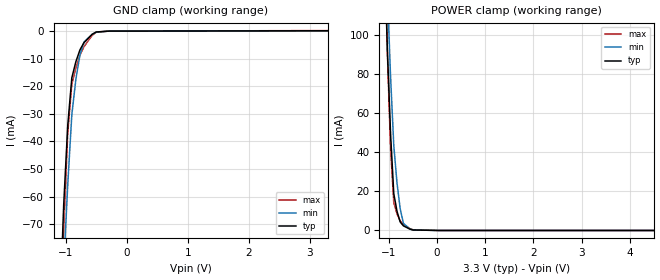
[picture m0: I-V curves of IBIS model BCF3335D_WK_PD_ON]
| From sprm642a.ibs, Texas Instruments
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|   Model Cell BCF3335D_WK_PD_ON
|BCF3335D_WK_PD_ON
[Model]   BCF3335D_WK_PD_ON
Model_type   Input
Polarity   Non-Inverting
Vinl =  0.8
Vinh =  2
C_comp   1.199917p   1.06526p   1.338254p
[Model Spec]
Vinl   0.8   0.8   0.8
Vinh   2   2   2
[Temperature Range]   25   155   -40
[Voltage Range]   3.3   2.97   3.63
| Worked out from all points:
|   GND clamp passes 1 mA (typ) near -0.55 V on its own axis
|   POWER clamp passes 1 mA (typ) near -0.59 V on its own axis
| Nom Voltages:
|   VDD=1.2, VDDS=3.3, VSS=0
| Min Voltages:
|   VDD=1.08, VDDS=2.97, VSS=0
| Max Voltages:
|   VDD=1.32, VDDS=3.63, VSS=0
[POWER_clamp]
|   voltage   I(typ)   I(min)   I(max)
-3.3V     2.333A     2.602A     3.083A
-1.1V     147.5mA    172.2mA    162.3mA
-1.033V   92.36mA    121.7mA    91.26mA
-966.7mV  49.51mA    78.85mA    41.92mA
-900mV    18.9mA     43.5mA     14.24mA
-833.3mV  9.846mA    24.38mA    8.545mA
-766.7mV  4.337mA    11.1mA     4.855mA
-700mV    2.37mA     3.662mA    3.173mA
-566.7mV  699.6uA    771.8uA    944.7uA
-500mV    248.7uA    286.4uA    332.8uA
33.33mV   0A         0A         0A
6.6V      0A         0A         0A
[GND_clamp]
|   voltage   I(typ)   I(min)   I(max)
-3.3V     -1.904A    -1.594A    -3.188A
-1.1V     -103.1mA   -119.1mA   -124mA
-1.033V   -62.89mA   -85.19mA   -71.77mA
-966.7mV  -34.16mA   -55.6mA    -36.88mA
-900mV    -16.94mA   -30.33mA   -19.31mA
-833.3mV  -11.09mA   -17.42mA   -13.31mA
-766.7mV  -6.831mA   -8.646mA   -8.753mA
-700mV    -4.166mA   -4.015mA   -5.633mA
-566.7mV  -1.181mA   -1.18mA    -1.554mA
-500mV    -336uA     -449.6uA   -399.2uA
-300mV    -27.98uA   -20.4uA    -40.75uA
3.3V      107.2uA    58.03uA    177.9uA
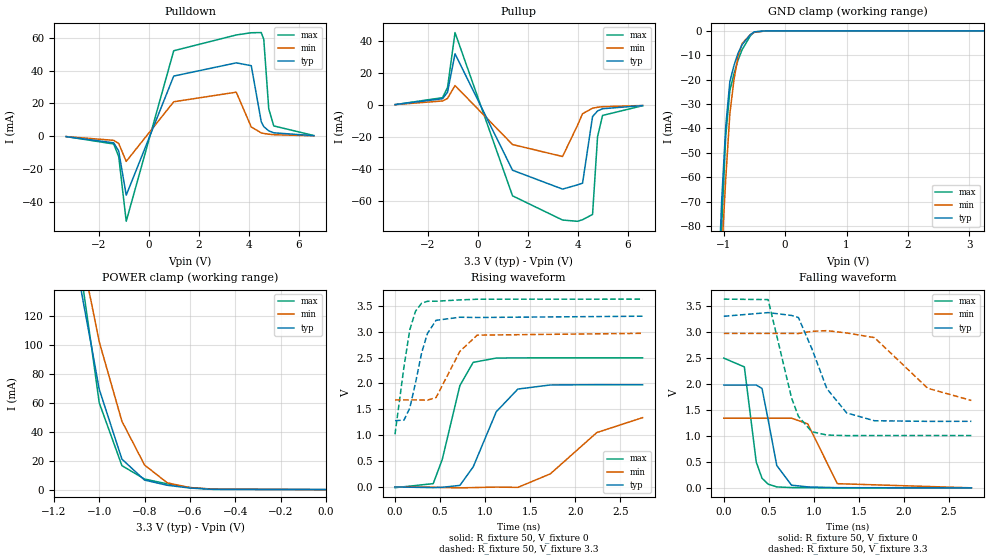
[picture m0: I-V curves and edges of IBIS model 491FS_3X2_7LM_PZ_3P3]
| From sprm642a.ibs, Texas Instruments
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|   Model Cell 491FS_3X2_7LM_PZ_3P3
|BQ0491FS_3X2_7LM_PZ_3P3
[Model]   491FS_3X2_7LM_PZ_3P3
Model_type   I/O
Polarity   Non-Inverting
Enable   Active-Low
Vinl =  1.25
Vinh =  1.65
Cref =  15.0001pF
Rref =  101.0000M
Vref =  0V
Vmeas =  1.65
C_comp   1.2p   1.2p   1.2p
[Model Spec]
Vinl   1.25   1.12   1.38
Vinh   1.65   1.45   1.75
[Temperature Range]   25   155   -40
[Voltage Range]   3.3   2.97   3.63
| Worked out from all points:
|   slope of the pulldown table from 0 to 0.495 V, typ, clamps not added: 22 ohm
|   slope of the pullup table from 0 to 0.495 V, typ, clamps not added: 26.9 ohm
|   GND clamp passes 1 mA (typ) near -0.53 V on its own axis
|   POWER clamp passes 1 mA (typ) near -0.59 V on its own axis
|   rising waveform, R_fixture 50, V_fixture 0: 20-80 % time 300ps typ, 528ps min, 211ps max; typ from 0 V to 1.98 V
|   rising waveform, R_fixture 50, V_fixture 3.3: 20-80 % time 158ps typ, 218ps min, 133ps max; typ from 1.28 V to 3.3 V
|   falling waveform, R_fixture 50, V_fixture 0: 20-80 % time 129ps typ, 180ps min, 108ps max; typ from 1.98 V to 0 V
|   falling waveform, R_fixture 50, V_fixture 3.3: 20-80 % time 290ps typ, 459ps min, 208ps max; typ from 3.3 V to 1.28 V
[POWER_clamp]
|   voltage   I(typ)   I(min)   I(max)
-3.3V     2.375A     2.63A      3.153A
-1.1V     156mA      180.2mA    173.4mA
-1.067V   127.2mA    154.3mA    135.6mA
-1.033V   98.41mA    128.4mA    97.92mA
-1V       69.61mA    102.5mA    60.2mA
-900mV    21.13mA    47.41mA    16.61mA
-800mV    6.576mA    17mA       7.309mA
-700mV    2.999mA    4.688mA    3.99mA
-600mV    1.087mA    1.404mA    1.425mA
-500mV    187uA      358.1uA    203.4uA
0V        311.4pA    5.945nA    272.3pA
[Pulldown]
|   voltage   I(typ)   I(min)   I(max)
-3.3V     -269.8uA   -248.1uA   -260.2uA
-1.4V     -4.056mA   -2.548mA   -4.78mA
-1.2V     -9.104mA   -4.482mA   -12.53mA
-900mV    -36.12mA   -15.43mA   -52.08mA
1V        36.78mA    21.07mA    52.28mA
3.5V      44.86mA    26.92mA    61.93mA
4.1V      43.14mA    5.644mA    63.29mA
4.5V      8.805mA    2.025mA    63.4mA
4.6V      5.861mA    1.678mA    59.29mA
4.8V      3.241mA    1.203mA    16.69mA
5V        2.072mA    900.6uA    6.272mA
6.6V      302.2uA    232.4uA    414.2uA
[Pullup]
|   voltage   I(typ)   I(min)   I(max)
-3.3V     296.7uA    284.3uA    270.4uA
-1.4V     3.996mA    2.582mA    4.655mA
-1.2V     8.017mA    4.201mA    10.97mA
-900mV    32.15mA    12.24mA    45.44mA
1.4V      -40.82mA   -24.72mA   -56.86mA
3.4V      -52.65mA   -32.22mA   -72.03mA
4V        -49.98mA   -12.64mA   -72.82mA
4.2V      -48.91mA   -5.386mA   -71.83mA
4.6V      -7.16mA    -1.965mA   -68.52mA
4.8V      -3.684mA   -1.373mA   -19.8mA
5V        -2.282mA   -1.01mA    -6.487mA
6.6V      -316.6uA   -254.8uA   -401.1uA
[GND_clamp]
|   voltage   I(typ)   I(min)   I(max)
-3.3V     -1.947A    -1.623A    -3.254A
-1.1V     -112mA     -127mA     -135.8mA
-1.033V   -69.61mA   -91.63mA   -80.19mA
-966.7mV  -39.23mA   -60.62mA   -43.11mA
-900mV    -20.86mA   -34.02mA   -24.52mA
-833.3mV  -14.26mA   -20.12mA   -17.61mA
-766.7mV  -9.194mA   -10.52mA   -12.01mA
-700mV    -5.668mA   -5.208mA   -7.706mA
-566.7mV  -1.566mA   -1.573mA   -2.055mA
-500mV    -402.3uA   -585.8uA   -459.7uA
-300mV    -821.9nA   -7.17uA    -404.6nA
3.233V    296.5pA    4.008uA    206.9pA
[Ramp]
| variable   typ   min   max
dV/dt_f   1.261151/0.2949777n  0.8125987/0.4793783n   1.631167/0.2132288n
dV/dt_r   1.201736/0.3055428n  0.8157639/0.5348505n   1.514657/0.207979n
R_load = 50
[Rising Waveform]
R_fixture = 50
V_fixture = 0
V_fixture_min = 0
V_fixture_max = 0
|   time   V(typ)   V(min)   V(max)
0s        -24.54uV   10.63uV    -14.63mV
424ps     -13.78mV   -3.257mV   63.95mV
524ps     -7.093mV   -11.97mV   527mV
720ps     29.58mV    -17.98mV   1.959V
868ps     387.7mV    -12.57mV   2.408V
1.124ns   1.453V     -3.016mV   2.491V
1.364ns   1.892V     -8.711mV   2.494V
1.724ns   1.971V     252.6mV    2.495V
2.24ns    1.976V     1.051V     2.495V
2.748ns   1.975V     1.339V     2.495V
[Rising Waveform]
R_fixture = 50
V_fixture = 3.3
V_fixture_min = 2.97
V_fixture_max = 3.63
|   time   V(typ)   V(min)   V(max)
0s        1.281V     1.682V     1.018V
100ps     1.292V     1.682V     2.327V
164ps     1.524V     1.682V     3.037V
228ps     2.014V     1.682V     3.398V
296ps     2.595V     1.681V     3.552V
360ps     2.966V     1.677V     3.588V
456ps     3.221V     1.728V     3.59V
720ps     3.28V      2.62V      3.615V
912ps     3.275V     2.934V     3.628V
2.748ns   3.3V       2.969V     3.63V
[Falling Waveform]
R_fixture = 50
V_fixture = 0
V_fixture_min = 0
V_fixture_max = 0
|   time   V(typ)   V(min)   V(max)
0s        1.977V     1.34V      2.495V
228ps     1.977V     1.34V      2.327V
360ps     1.978V     1.34V      497.8mV
424ps     1.912V     1.34V      186mV
492ps     1.313V     1.34V      71.31mV
588ps     429.9mV    1.34V      18.16mV
752ps     51.68mV    1.34V      5.391mV
932ps     18.34mV    1.231V     2.379mV
1.26ns    3.521mV    80.53mV    495.6uV
2.748ns   98.08uV    534.9uV    -8.176uV
[Falling Waveform]
R_fixture = 50
V_fixture = 3.3
V_fixture_min = 2.97
V_fixture_max = 3.63
|   time   V(typ)   V(min)   V(max)
0s        3.3V       2.97V      3.63V
492ps     3.371V     2.97V      3.621V
752ps     3.316V     2.97V      1.73V
828ps     3.276V     2.969V     1.377V
976ps     2.683V     3.01V      1.081V
1.144ns   1.907V     3.024V     1.016V
1.364ns   1.441V     2.979V     1.005V
1.672ns   1.291V     2.89V      1.006V
2.264ns   1.279V     1.915V     1.007V
2.748ns   1.28V      1.681V     1.006V
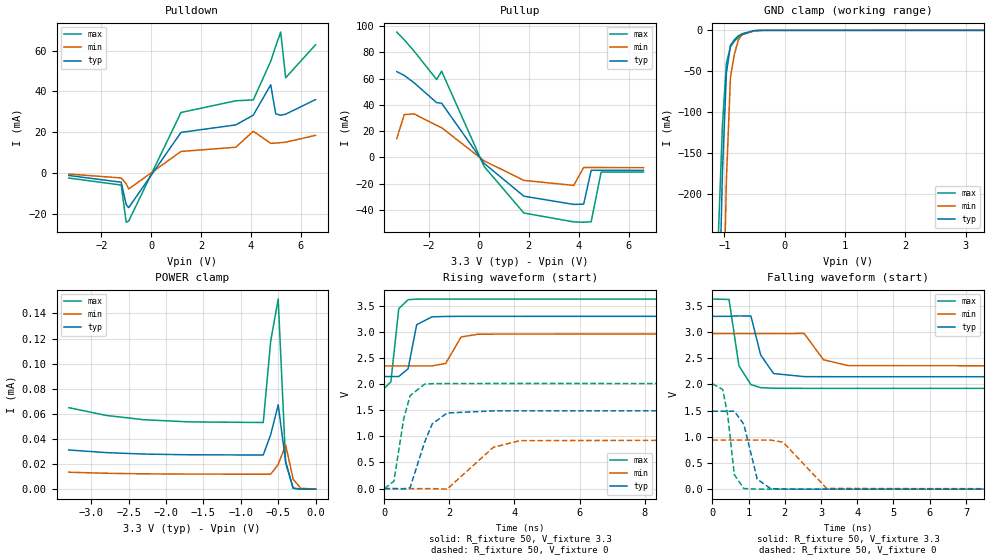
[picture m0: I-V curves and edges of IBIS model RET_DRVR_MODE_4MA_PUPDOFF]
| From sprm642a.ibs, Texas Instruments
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|   Model Cell RET_DRVR_MODE_4MA_PUPDOFF
|RET_DRVR_MODE_4MA_PUPDOFF
[Model]   RET_DRVR_MODE_4MA_PUPDOFF
Model_type   I/O
Polarity   Non-Inverting
Enable   Active-Low
Vinl =  0.8
Vinh =  2
Cref =  15.0000pF
Rref =  100.0000M
Vref =  0V
Vmeas =  1.65
C_comp   5.345208p   4.561426p   6.022817p
[Model Spec]
Vinl   0.8   0.8   0.8
Vinh   2   2   2
[Temperature Range]   25   155   -40
[Voltage Range]   3.3   2.97   3.63
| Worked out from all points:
|   slope of the pulldown table from 0 to 0.495 V, typ, clamps not added: 47.6 ohm
|   slope of the pullup table from 0 to 0.495 V, typ, clamps not added: 46.2 ohm
|   GND clamp passes 1 mA (typ) near -0.55 V on its own axis
|   rising waveform, R_fixture 50, V_fixture 3.3: 20-80 % time 194ps typ, 280ps min, 151ps max; typ from 2.15 V to 3.3 V
|   rising waveform, R_fixture 50, V_fixture 0: 20-80 % time 455ps typ, 811ps min, 333ps max; typ from 0 V to 1.49 V
|   falling waveform, R_fixture 50, V_fixture 3.3: 20-80 % time 263ps typ, 365ps min, 230ps max; typ from 3.3 V to 2.15 V
|   falling waveform, R_fixture 50, V_fixture 0: 20-80 % time 300ps typ, 541ps min, 197ps max; typ from 1.49 V to 0 V
| Nom Voltages:
|   BIASFET=3.3, VDD=1.2, VDDS=3.3, VSS=0
| Min Voltages:
|   BIASFET=2.97, VDD=1.08, VDDS=2.97, VSS=0
| Max Voltages:
|   BIASFET=3.63, VDD=1.32, VDDS=3.63, VSS=0
[POWER_clamp]
|   voltage   I(typ)   I(min)   I(max)
-3.3V     31.22uA    13.5uA     64.95uA
-2.8V     29.13uA    12.67uA    58.77uA
-2.3V     27.98uA    12.22uA    55.36uA
-1.7V     27.4uA     12.01uA    53.62uA
-700mV    27.24uA    11.95uA    53.12uA
-600mV    43.52uA    11.94uA    118.2uA
-500mV    67.2uA     19.79uA    151.5uA
-400mV    21.58uA    35.09uA    21.1uA
-300mV    927.4nA    7.958uA    611.4nA
-200mV    28.93nA    716.3nA    11.51nA
0V        696.9pA    39.48nA    568pA
[Pulldown]
|   voltage   I(typ)   I(min)   I(max)
-3.3V     -1.162mA   -442.5uA   -2.413mA
-1.2V     -4.448mA   -2.37mA    -5.833mA
-1V       -15.42mA   -5.267mA   -24.03mA
-900mV    -16.9mA    -7.758mA   -23.48mA
1.2V      19.95mA    10.62mA    29.71mA
3.4V      23.64mA    12.69mA    35.45mA
4.1V      28.41mA    20.51mA    35.87mA
4.8V      43.29mA    14.6mA     54.81mA
5V        29.04mA    14.73mA    62.21mA
5.2V      28.35mA    14.92mA    69.1mA
5.4V      28.9mA     15.16mA    46.73mA
6.6V      36.05mA    18.53mA    62.9mA
[Pullup]
|   voltage   I(typ)   I(min)   I(max)
-3.3V     65.33mA    14.31mA    95.47mA
-3V       62.41mA    32.57mA    89.6mA
-2.6V     56.73mA    33.05mA    80.83mA
-1.7V     41.66mA    24.3mA     59.29mA
-1.5V     41.23mA    22.57mA    65.63mA
200mV     -4.548mA   -2.626mA   -6.86mA
1.8V      -29.65mA   -17.6mA    -42.48mA
3.8V      -35.93mA   -21.45mA   -49.25mA
4.2V      -35.7mA    -7.748mA   -49.48mA
4.5V      -9.896mA   -7.768mA   -49.16mA
4.9V      -9.898mA   -7.8mA     -11.24mA
6.6V      -9.969mA   -7.94mA    -11.25mA
[GND_clamp]
|   voltage   I(typ)   I(min)   I(max)
-3.3V     -16.36A    -15.08A    -17.18A
-1.1V     -382.1mA   -717.8mA   -250.1mA
-1.033V   -173.3mA   -402.2mA   -116.4mA
-966.7mV  -52.02mA   -182.1mA   -39.81mA
-900mV    -18.21mA   -57.43mA   -20.34mA
-833.3mV  -11.36mA   -28.88mA   -13.17mA
-766.7mV  -6.618mA   -11.27mA   -8.134mA
-700mV    -3.983mA   -4.59mA    -5.247mA
-500mV    -328.3uA   -481.4uA   -374.5uA
-366.7mV  -15.94uA   -50.74uA   -14.83uA
3.3V      697pA      15.84uA    426.1pA
[Ramp]
| variable   typ   min   max
dV/dt_f 0.70108472/0.26467362n  0.3775134/0.36797817n  1.0337594/0.2297899n
dV/dt_r 0.90140012/0.45748411n 0.56935959/0.81782891n  1.2149327/0.33385389n
R_load = 50
[Rising Waveform]
R_fixture = 50
V_fixture = 3.3
V_fixture_min = 2.97
V_fixture_max = 3.63
|   time   V(typ)   V(min)   V(max)
0s        2.146V     2.35V      1.924V
197.7ps   2.146V     2.35V      2.043V
440.5ps   2.146V     2.35V      3.446V
728.2ps   2.296V     2.35V      3.618V
990.8ps   3.138V     2.35V      3.628V
1.46ns    3.289V     2.35V      3.63V
1.883ns   3.297V     2.397V     3.63V
2.357ns   3.299V     2.904V     3.63V
2.889ns   3.299V     2.958V     3.63V
20.14ns   3.3V       2.97V      3.63V
[Rising Waveform]
R_fixture = 50
V_fixture = 0
V_fixture_min = 0
V_fixture_max = 0
|   time   V(typ)   V(min)   V(max)
0s        0V         0V         0V
291.1ps   0V         0V         142.4mV
593.2ps   -7.748mV   0V         1.338V
789.3ps   16.48mV    0V         1.78V
1.231ns   882.3mV    0V         1.999V
1.47ns    1.239V     0V         2.01V
1.927ns   1.448V     -10.91mV   2.012V
3.351ns   1.488V     791.6mV    2.013V
4.174ns   1.489V     918.6mV    2.013V
20.01ns   1.489V     937.6mV    2.012V
[Falling Waveform]
R_fixture = 50
V_fixture = 3.3
V_fixture_min = 2.97
V_fixture_max = 3.63
|   time   V(typ)   V(min)   V(max)
0s        3.3V       2.97V      3.63V
460.3ps   3.3V       2.97V      3.623V
733.6ps   3.309V     2.97V      2.355V
1.064ns   3.305V     2.97V      1.997V
1.333ns   2.563V     2.97V      1.939V
1.689ns   2.208V     2.97V      1.926V
2.531ns   2.149V     2.974V     1.925V
3.07ns    2.148V     2.471V     1.925V
3.746ns   2.147V     2.359V     1.925V
20.14ns   2.146V     2.35V      1.925V
[Falling Waveform]
R_fixture = 50
V_fixture = 0
V_fixture_min = 0
V_fixture_max = 0
|   time   V(typ)   V(min)   V(max)
0s        1.489V     937.2mV    2.013V
287.6ps   1.489V     937.2mV    1.902V
423.7ps   1.489V     937.2mV    1.414V
606.4ps   1.489V     937.2mV    276.1mV
868.9ps   1.239V     937.2mV    12.33mV
1.239ns   190.6mV    937.2mV    0V
1.608ns   10.16mV    937mV      0V
1.952ns   2.09mV     897.9mV    0V
3.157ns   0V         12.74mV    0V
20.01ns   0V         0V         0V
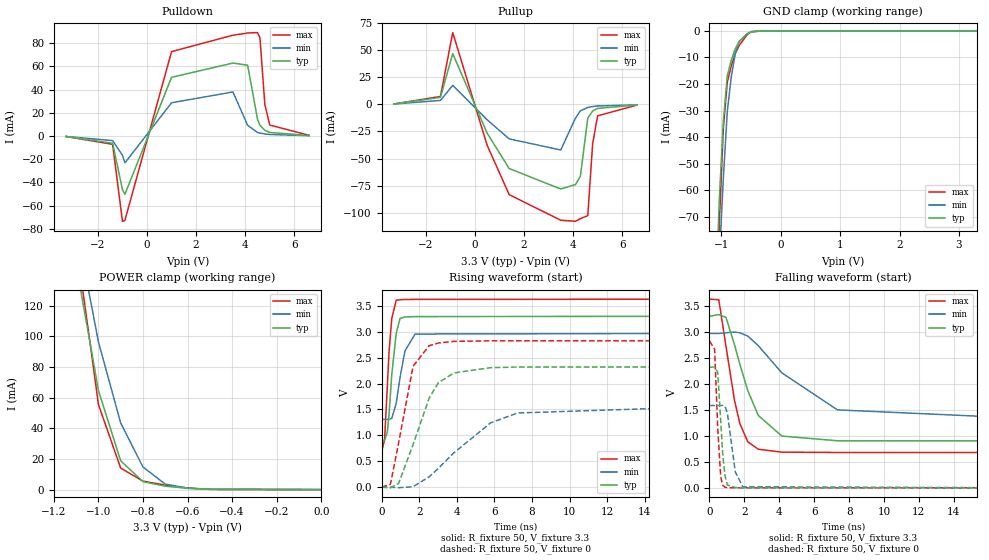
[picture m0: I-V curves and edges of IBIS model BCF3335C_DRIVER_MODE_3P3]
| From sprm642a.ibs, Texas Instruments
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|   Model Cell BCF3335C_DRIVER_MODE_3P3
|BCF3335C_DRIVER_MODE_3P3
[Model]   BCF3335C_DRIVER_MODE_3P3
Model_type   I/O
Polarity   Non-Inverting
Enable   Active-Low
Vinl =  0.8
Vinh =  2
Cref =  15.0000pF
Rref =  100.0000M
Vref =  0V
Vmeas =  1.65
C_comp   1.21278p   1.078036p   1.350148p
[Model Spec]
Vinl   0.8   0.8   0.8
Vinh   2   2   2
[Temperature Range]   25   155   -40
[Voltage Range]   3.3   2.97   3.63
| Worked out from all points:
|   slope of the pulldown table from 0 to 0.495 V, typ, clamps not added: 16.3 ohm
|   slope of the pullup table from 0 to 0.495 V, typ, clamps not added: 18.9 ohm
|   GND clamp passes 1 mA (typ) near -0.56 V on its own axis
|   POWER clamp passes 1 mA (typ) near -0.61 V on its own axis
|   rising waveform, R_fixture 50, V_fixture 3.3: 20-80 % time 324ps typ, 461ps min, 266ps max; typ from 0.904 V to 3.3 V
|   rising waveform, R_fixture 50, V_fixture 0: 20-80 % time 1.37ns typ, 3.07ns min, 863ps max; typ from 0 V to 2.32 V
|   falling waveform, R_fixture 50, V_fixture 3.3: 20-80 % time 1.44ns typ, 3.22ns min, 907ps max; typ from 3.3 V to 0.904 V
|   falling waveform, R_fixture 50, V_fixture 0: 20-80 % time 246ps typ, 378ps min, 201ps max; typ from 2.32 V to 0 V
| Nom Voltages:
|   VDD=1.2, VDDS=3.3, VSS=0
| Min Voltages:
|   VDD=1.08, VDDS=2.97, VSS=0
| Max Voltages:
|   VDD=1.32, VDDS=3.63, VSS=0
[POWER_clamp]
|   voltage   I(typ)   I(min)   I(max)
-3.3V     2.319A     2.596A     3.052A
-1.1V     147.6mA    172.2mA    162.5mA
-1.067V   120mA      147mA      126.9mA
-1.033V   92.39mA    121.8mA    91.25mA
-1V       64.8mA     96.55mA    55.64mA
-900mV    18.81mA    43.51mA    14.07mA
-800mV    5.217mA    14.79mA    5.52mA
-700mV    2.265mA    3.617mA    2.996mA
-600mV    818.1uA    964.5uA    1.072mA
-500mV    141.2uA    235.4uA    153.9uA
0V        61.2pA     4.167nA    14.64pA
[Pulldown]
|   voltage   I(typ)   I(min)   I(max)
-3.3V     -391.6uA   -361.2uA   -374.3uA
-1.4V     -6.232mA   -3.922mA   -7.12mA
-1V       -46.14mA   -16.61mA   -73.47mA
-900mV    -50.18mA   -23.11mA   -72.68mA
1V        50.59mA    28.67mA    72.75mA
3.5V      62.89mA    37.99mA    86.89mA
4.1V      61.03mA    9.214mA    88.75mA
4.5V      14.6mA     3.072mA    89.16mA
4.6V      9.297mA    2.529mA    84.77mA
4.8V      4.929mA    1.797mA    27.22mA
5V        3.1mA      1.339mA    9.48mA
6.6V      439.9uA    335.7uA    600uA
[Pullup]
|   voltage   I(typ)   I(min)   I(max)
-3.3V     459.5uA    394.7uA    413.2uA
-1.4V     6.562mA    3.722mA    7.377mA
-900mV    46.98mA    17.64mA    66.44mA
500mV     -26.44mA   -14.16mA   -37.6mA
1.4V      -59.25mA   -31.82mA   -83.37mA
3.5V      -78.14mA   -42.09mA   -107mA
4.1V      -74.05mA   -12.61mA   -108mA
4.3V      -66.33mA   -5.866mA   -105.6mA
4.6V      -12.76mA   -2.802mA   -102.8mA
4.8V      -6.084mA   -1.937mA   -36.14mA
5V        -3.668mA   -1.416mA   -10.53mA
6.6V      -489.4uA   -345.7uA   -614.6uA
[GND_clamp]
|   voltage   I(typ)   I(min)   I(max)
-3.3V     -1.89A     -1.587A    -3.158A
-1.1V     -103.2mA   -119.1mA   -124.2mA
-1.033V   -62.94mA   -85.23mA   -71.86mA
-966.7mV  -34.17mA   -55.63mA   -36.88mA
-900mV    -16.92mA   -30.33mA   -19.28mA
-833.3mV  -11.06mA   -17.41mA   -13.25mA
-766.7mV  -6.784mA   -8.632mA   -8.674mA
-700mV    -4.107mA   -3.993mA   -5.546mA
-566.7mV  -1.13mA    -1.153mA   -1.479mA
-500mV    -290.2uA   -424.2uA   -331.9uA
-300mV    -598.5nA   -5.196uA   -296.8nA
3.3V      61.2pA     6.786uA    8.136pA
[Ramp]
| variable   typ   min   max
dV/dt_f   1.461786/1.4476561n  1.0135907/3.246082n   1.7954386/0.91538426n
dV/dt_r  1.4029813/1.3750139n 0.95806656/3.0834157n  1.7045214/0.86702444n
R_load = 50
[Rising Waveform]
R_fixture = 50
V_fixture = 3.3
V_fixture_min = 2.97
V_fixture_max = 3.63
|   time   V(typ)   V(min)   V(max)
0s        903.7mV    1.309V     681.8mV
156.7ps   905.2mV    1.31V      916.3mV
297.1ps   1.058V     1.309V     1.912V
392.9ps   1.396V     1.308V     2.606V
537.9ps   2.175V     1.327V     3.254V
774.4ps   2.968V     1.615V     3.609V
976.8ps   3.255V     2.115V     3.618V
1.237ns   3.286V     2.626V     3.623V
1.778ns   3.293V     2.956V     3.625V
20.02ns   3.3V       2.97V      3.63V
[Rising Waveform]
R_fixture = 50
V_fixture = 0
V_fixture_min = 0
V_fixture_max = 0
|   time   V(typ)   V(min)   V(max)
0s        0V         0V         0V
464.7ps   -13.07mV   0V         54.97mV
902.2ps   72.68mV    -10.01mV   852.8mV
1.672ns   822.7mV    9.485mV    2.334V
2.527ns   1.72V      200.3mV    2.732V
3.029ns   2.022V     366.6mV    2.783V
3.856ns   2.206V     667.1mV    2.815V
5.794ns   2.307V     1.241V     2.825V
7.222ns   2.319V     1.432V     2.825V
20.01ns   2.321V     1.584V     2.825V
[Falling Waveform]
R_fixture = 50
V_fixture = 3.3
V_fixture_min = 2.97
V_fixture_max = 3.63
|   time   V(typ)   V(min)   V(max)
0s        3.3V       2.97V      3.63V
535.7ps   3.333V     2.97V      3.618V
947.9ps   3.277V     2.983V     2.717V
1.438ns   2.75V      2.998V     1.678V
1.743ns   2.375V     2.983V     1.235V
2.194ns   1.871V     2.92V      886mV
2.798ns   1.393V     2.734V     742.9mV
4.145ns   996.2mV    2.213V     687.1mV
7.332ns   905.7mV    1.5V       680.6mV
20.02ns   903.6mV    1.309V     680.8mV
[Falling Waveform]
R_fixture = 50
V_fixture = 0
V_fixture_min = 0
V_fixture_max = 0
|   time   V(typ)   V(min)   V(max)
0s        2.321V     1.584V     2.825V
295.7ps   2.323V     1.583V     2.667V
470.9ps   2.229V     1.583V     1.17V
643.4ps   1.299V     1.585V     215mV
753.8ps   669mV      1.586V     52.35mV
889ps     231.8mV    1.57V      12.31mV
1.029ns   54.15mV    1.429V     4.593mV
1.481ns   7.104mV    304.9mV    0V
1.915ns   2.84mV     19.68mV    0V
20.01ns   0V         0V         0V
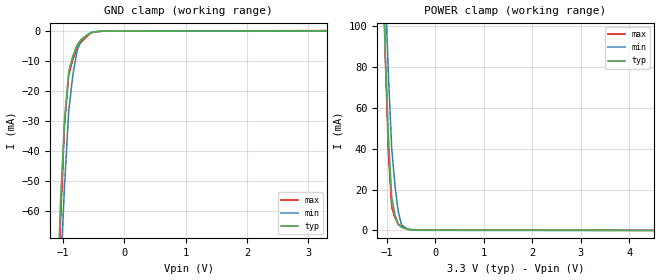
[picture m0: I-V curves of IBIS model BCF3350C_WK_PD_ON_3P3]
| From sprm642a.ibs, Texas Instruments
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|   Model Cell BCF3350C_WK_PD_ON_3P3
|BCF3350C_WK_PD_ON_3P3
[Model]   BCF3350C_WK_PD_ON_3P3
Model_type   Input
Polarity   Non-Inverting
Vinl =  0.8
Vinh =  2
C_comp   1.081618p   0.946736p   1.221412p
[Model Spec]
Vinl   0.8   0.8   0.8
Vinh   2   2   2
[Temperature Range]   25   155   -40
[Voltage Range]   3.3   2.97   3.63
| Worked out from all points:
|   GND clamp passes 1 mA (typ) near -0.58 V on its own axis
|   POWER clamp passes 1 mA (typ) near -0.64 V on its own axis
| Nom Voltages:
|   VDD=1.2, VDDS=3.3, VSS=0
| Min Voltages:
|   VDD=1.08, VDDS=2.97, VSS=0
| Max Voltages:
|   VDD=1.32, VDDS=3.63, VSS=0
[POWER_clamp]
|   voltage   I(typ)   I(min)   I(max)
-3.3V     2.318A     2.595A     3.049A
-1.1V     141.5mA    168mA      152.4mA
-1.033V   87.22mA    117.8mA    84.5mA
-966.7mV  45.46mA    75.19mA    37.47mA
-900mV    16.26mA    40.27mA    11.33mA
-833.3mV  7.927mA    21.99mA    6.203mA
-766.7mV  3.013mA    9.498mA    3.099mA
-700mV    1.521mA    2.801mA    2.021mA
-566.7mV  472.3uA    527.3uA    648.9uA
-366.7mV  111.4uA    66.02uA    181.9uA
6.6V      0A         0A         0A
[GND_clamp]
|   voltage   I(typ)   I(min)   I(max)
-3.3V     -1.888A    -1.585A    -3.154A
-1.1V     -95.79mA   -113.9mA   -112.1mA
-1.033V   -56.71mA   -80.31mA   -63.62mA
-966.7mV  -29.26mA   -51.23mA   -31.17mA
-900mV    -13.43mA   -26.68mA   -14.76mA
-833.3mV  -8.27mA    -14.79mA   -9.517mA
-766.7mV  -4.725mA   -6.876mA   -5.842mA
-700mV    -2.797mA   -2.931mA   -3.733mA
-566.7mV  -794.1uA   -808.3uA   -1.042mA
-500mV    -234.8uA   -305.8uA   -282.8uA
-366.7mV  -42.38uA   -46.42uA   -57.66uA
3.3V      107.2uA    55.45uA    177.9uA
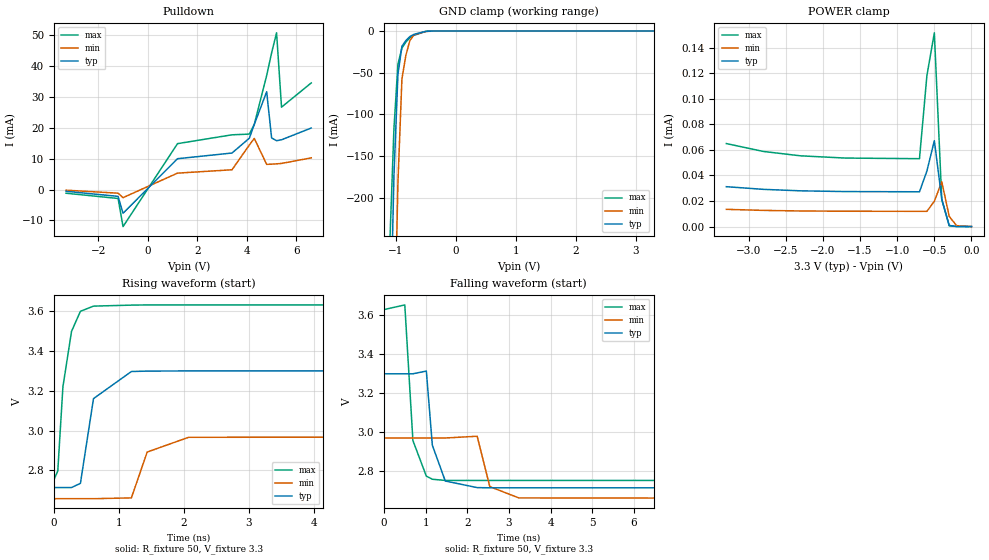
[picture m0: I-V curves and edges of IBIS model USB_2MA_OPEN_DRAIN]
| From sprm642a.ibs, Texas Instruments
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|   Model Cell USB_2MA_OPEN_DRAIN
|USB_2MA_OPEN_DRAIN
[Model]   USB_2MA_OPEN_DRAIN
Model_type   I/O_open_drain
Polarity   Inverting
Enable   Active-Low
Vinl =  0.8
Vinh =  2
Cref =  15.0000pF
Rref =  100.0000M
Vref =  0V
Vmeas =  1.65
C_comp   5.34973p   4.565931p   6.027791p
[Model Spec]
Vinl   0.8   0.8   0.8
Vinh   2   2   2
[Temperature Range]   25   155   -40
[Voltage Range]   3.3   2.97   3.63
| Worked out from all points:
|   slope of the pulldown table from 0 to 0.495 V, typ, clamps not added: 95.1 ohm
|   GND clamp passes 1 mA (typ) near -0.55 V on its own axis
|   rising waveform, R_fixture 50, V_fixture 3.3: 20-80 % time 190ps typ, 224ps min, 160ps max; typ from 2.71 V to 3.3 V
|   falling waveform, R_fixture 50, V_fixture 3.3: 20-80 % time 189ps typ, 222ps min, 168ps max; typ from 3.3 V to 2.71 V
| Nom Voltages:
|   BIASFET=3.3, VDD=1.2, VDDS=3.3, VSS=0
| Min Voltages:
|   BIASFET=2.97, VDD=1.08, VDDS=2.97, VSS=0
| Max Voltages:
|   BIASFET=3.63, VDD=1.32, VDDS=3.63, VSS=0
[POWER_clamp]
|   voltage   I(typ)   I(min)   I(max)
-3.3V     31.22uA    13.5uA     64.95uA
-2.8V     29.13uA    12.67uA    58.77uA
-2.3V     27.98uA    12.22uA    55.36uA
-1.7V     27.4uA     12.01uA    53.62uA
-700mV    27.24uA    11.95uA    53.12uA
-600mV    43.52uA    11.94uA    118.2uA
-500mV    67.21uA    19.79uA    151.6uA
-400mV    21.58uA    35.11uA    21.1uA
-300mV    927.4nA    7.959uA    611.4nA
-200mV    28.93nA    716.3nA    11.51nA
0V        696.9pA    39.48nA    568pA
[Pulldown]
|   voltage   I(typ)   I(min)   I(max)
-3.3V     -580.7uA   -221.2uA   -1.206mA
-1.2V     -2.224mA   -1.185mA   -2.903mA
-1V       -7.701mA   -2.63mA    -12.01mA
1.2V      9.981mA    5.309mA    14.86mA
3.4V      11.82mA    6.396mA    17.72mA
4.1V      16.62mA    14.41mA    17.95mA
4.3V      21.11mA    16.55mA    21.11mA
4.8V      31.66mA    8.148mA    36.94mA
5V        16.71mA    8.219mA    44.27mA
5.2V      15.82mA    8.317mA    50.76mA
5.4V      16.11mA    8.446mA    26.68mA
6.6V      19.93mA    10.26mA    34.53mA
[GND_clamp]
|   voltage   I(typ)   I(min)   I(max)
-3.3V     -16.36A    -15.08A    -17.18A
-1.1V     -382.1mA   -717.8mA   -250.1mA
-1.033V   -173.3mA   -402.2mA   -116.4mA
-966.7mV  -52.02mA   -182.1mA   -39.81mA
-900mV    -18.21mA   -57.43mA   -20.34mA
-833.3mV  -11.36mA   -28.88mA   -13.17mA
-766.7mV  -6.618mA   -11.27mA   -8.134mA
-700mV    -3.983mA   -4.59mA    -5.247mA
-500mV    -328.3uA   -481.4uA   -374.5uA
-366.7mV  -15.94uA   -50.74uA   -14.83uA
3.3V      696.9pA    15.85uA    426.1pA
[Ramp]
| variable   typ   min   max
dV/dt_f 0.36646067/0.18656318n  0.1967659/0.22197166n 0.54761634/0.16770422n
dV/dt_r 0.52375749/0.22147225n 0.31724293/0.30230588n 0.72404355/0.18738031n
R_load = 50
[Rising Waveform]
R_fixture = 50
V_fixture = 3.3
V_fixture_min = 2.97
V_fixture_max = 3.63
|   time   V(typ)   V(min)   V(max)
0s        2.714V     2.658V     2.752V
60.9ps    2.714V     2.658V     2.797V
139.9ps   2.714V     2.658V     3.219V
272ps     2.714V     2.658V     3.497V
409ps     2.735V     2.658V     3.598V
610.2ps   3.16V      2.658V     3.624V
1.193ns   3.296V     2.662V     3.629V
1.436ns   3.298V     2.892V     3.63V
2.074ns   3.299V     2.966V     3.63V
20.03ns   3.3V       2.97V      3.63V
[Falling Waveform]
R_fixture = 50
V_fixture = 3.3
V_fixture_min = 2.97
V_fixture_max = 3.63
|   time   V(typ)   V(min)   V(max)
0s        3.3V       2.97V      3.63V
500.2ps   3.3V       2.97V      3.654V
694.7ps   3.3V       2.97V      2.957V
1.017ns   3.314V     2.97V      2.774V
1.161ns   2.933V     2.97V      2.758V
1.471ns   2.749V     2.97V      2.752V
2.236ns   2.715V     2.979V     2.752V
2.54ns    2.714V     2.72V      2.752V
3.235ns   2.714V     2.662V     2.752V
20.03ns   2.714V     2.658V     2.752V
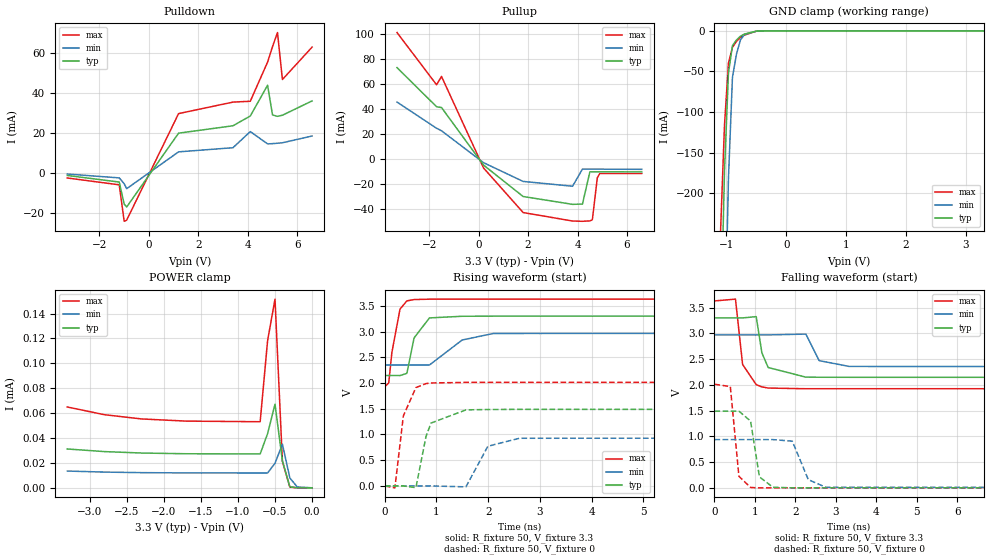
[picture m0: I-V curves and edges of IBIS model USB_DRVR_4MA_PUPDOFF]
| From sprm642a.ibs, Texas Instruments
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|   Model Cell USB_DRVR_4MA_PUPDOFF
|USB_DRVR_4MA_PUPDOFF
[Model]   USB_DRVR_4MA_PUPDOFF
Model_type   I/O
Polarity   Non-Inverting
Enable   Active-Low
Vinl =  0.8
Vinh =  2
Cref =  15.0000pF
Rref =  100.0000M
Vref =  0V
Vmeas =  1.65
C_comp   5.34973p   4.565931p   6.027791p
[Model Spec]
Vinl   0.8   0.8   0.8
Vinh   2   2   2
[Temperature Range]   25   155   -40
[Voltage Range]   3.3   2.97   3.63
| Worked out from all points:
|   slope of the pulldown table from 0 to 0.495 V, typ, clamps not added: 47.6 ohm
|   slope of the pullup table from 0 to 0.495 V, typ, clamps not added: 46.2 ohm
|   GND clamp passes 1 mA (typ) near -0.55 V on its own axis
|   rising waveform, R_fixture 50, V_fixture 3.3: 20-80 % time 196ps typ, 229ps min, 153ps max; typ from 2.15 V to 3.3 V
|   rising waveform, R_fixture 50, V_fixture 0: 20-80 % time 195ps typ, 284ps min, 167ps max; typ from 0 V to 1.49 V
|   falling waveform, R_fixture 50, V_fixture 3.3: 20-80 % time 205ps typ, 243ps min, 183ps max; typ from 3.3 V to 2.15 V
|   falling waveform, R_fixture 50, V_fixture 0: 20-80 % time 172ps typ, 280ps min, 125ps max; typ from 1.49 V to 0 V
| Nom Voltages:
|   BIASFET=3.3, VDD=1.2, VDDS=3.3, VSS=0
| Min Voltages:
|   BIASFET=2.97, VDD=1.08, VDDS=2.97, VSS=0
| Max Voltages:
|   BIASFET=3.63, VDD=1.32, VDDS=3.63, VSS=0
[POWER_clamp]
|   voltage   I(typ)   I(min)   I(max)
-3.3V     31.22uA    13.5uA     64.95uA
-2.8V     29.13uA    12.67uA    58.77uA
-2.3V     27.98uA    12.22uA    55.36uA
-1.7V     27.4uA     12.01uA    53.62uA
-700mV    27.24uA    11.95uA    53.12uA
-600mV    43.52uA    11.94uA    118.2uA
-500mV    67.21uA    19.79uA    151.6uA
-400mV    21.58uA    35.11uA    21.1uA
-300mV    927.4nA    7.959uA    611.4nA
-200mV    28.93nA    716.3nA    11.51nA
0V        696.9pA    39.48nA    568.3pA
[Pulldown]
|   voltage   I(typ)   I(min)   I(max)
-3.3V     -1.162mA   -442.5uA   -2.413mA
-1.2V     -4.448mA   -2.37mA    -5.833mA
-1V       -15.42mA   -5.267mA   -24.03mA
-900mV    -16.9mA    -7.758mA   -23.48mA
1.2V      19.95mA    10.62mA    29.71mA
3.4V      23.64mA    12.69mA    35.45mA
4.1V      28.51mA    20.74mA    35.87mA
4.8V      43.85mA    14.6mA     55.43mA
5V        29.04mA    14.73mA    63.13mA
5.2V      28.35mA    14.92mA    70.15mA
5.4V      28.9mA     15.16mA    46.73mA
6.6V      36.05mA    18.53mA    62.9mA
[Pullup]
|   voltage   I(typ)   I(min)   I(max)
-3.3V     73.38mA    45.83mA    101.4mA
-1.7V     42.1mA     24.9mA     59.66mA
-1.5V     41.44mA    22.89mA    66.29mA
200mV     -4.548mA   -2.626mA   -6.86mA
1.8V      -29.65mA   -17.6mA    -42.48mA
3.8V      -35.93mA   -21.45mA   -49.25mA
4.2V      -35.7mA    -7.748mA   -49.48mA
4.5V      -9.896mA   -7.768mA   -49.16mA
4.6V      -9.894mA   -7.776mA   -48.29mA
4.8V      -9.896mA   -7.792mA   -14.75mA
4.9V      -9.898mA   -7.8mA     -11.24mA
6.6V      -9.969mA   -7.94mA    -11.25mA
[GND_clamp]
|   voltage   I(typ)   I(min)   I(max)
-3.3V     -16.36A    -15.08A    -17.18A
-1.1V     -382.1mA   -717.8mA   -250.1mA
-1.033V   -173.3mA   -402.2mA   -116.4mA
-966.7mV  -52.02mA   -182.1mA   -39.81mA
-900mV    -18.21mA   -57.43mA   -20.34mA
-833.3mV  -11.36mA   -28.88mA   -13.17mA
-766.7mV  -6.618mA   -11.27mA   -8.134mA
-700mV    -3.983mA   -4.59mA    -5.247mA
-500mV    -328.3uA   -481.4uA   -374.5uA
-366.7mV  -15.94uA   -50.74uA   -14.83uA
3.3V      696.9pA    15.85uA    426.1pA
[Ramp]
| variable   typ   min   max
dV/dt_f 0.71606892/0.20269188n 0.38743512/0.24185261n  1.0546967/0.18146274n
dV/dt_r 0.91898113/0.19572134n 0.57962754/0.28813413n  1.2382929/0.16793875n
R_load = 50
[Rising Waveform]
R_fixture = 50
V_fixture = 3.3
V_fixture_min = 2.97
V_fixture_max = 3.63
|   time   V(typ)   V(min)   V(max)
0s        2.146V     2.35V      1.925V
76.7ps    2.146V     2.35V      2.003V
138ps     2.146V     2.35V      2.597V
294.6ps   2.145V     2.35V      3.436V
427.5ps   2.188V     2.35V      3.596V
566.9ps   2.877V     2.35V      3.622V
864.2ps   3.265V     2.35V      3.629V
1.497ns   3.297V     2.836V     3.63V
2.101ns   3.299V     2.963V     3.63V
20.04ns   3.3V       2.97V      3.63V
[Rising Waveform]
R_fixture = 50
V_fixture = 0
V_fixture_min = 0
V_fixture_max = 0
|   time   V(typ)   V(min)   V(max)
0s        0V         0V         0V
195.2ps   0V         0V         -37.32mV
359.4ps   0V         0V         1.363V
602.4ps   -33.11mV   0V         1.912V
798ps     964.2mV    0V         1.989V
895.2ps   1.222V     0V         2.001V
1.569ns   1.478V     -17.93mV   2.012V
1.994ns   1.485V     771mV      2.012V
2.604ns   1.488V     926.1mV    2.012V
20.01ns   1.489V     937.6mV    2.012V
[Falling Waveform]
R_fixture = 50
V_fixture = 3.3
V_fixture_min = 2.97
V_fixture_max = 3.63
|   time   V(typ)   V(min)   V(max)
0s        3.3V       2.97V      3.63V
518.5ps   3.3V       2.97V      3.665V
694.4ps   3.3V       2.97V      2.396V
1.031ns   3.325V     2.97V      2.004V
1.17ns    2.625V     2.97V      1.961V
1.326ns   2.337V     2.97V      1.938V
2.257ns   2.15V      2.986V     1.925V
2.586ns   2.148V     2.471V     1.925V
3.326ns   2.147V     2.358V     1.925V
20.04ns   2.146V     2.35V      1.925V
[Falling Waveform]
R_fixture = 50
V_fixture = 0
V_fixture_min = 0
V_fixture_max = 0
|   time   V(typ)   V(min)   V(max)
0s        1.489V     937.2mV    2.013V
391.2ps   1.489V     937.2mV    1.966V
603.5ps   1.489V     937.2mV    225mV
891.6ps   1.297V     937.2mV    7.365mV
1.11ns    214.1mV    937.2mV    0V
1.442ns   12.66mV    937.1mV    0V
1.922ns   0V         907mV      0V
2.317ns   0V         160.6mV    0V
2.744ns   0V         12.57mV    0V
20.01ns   0V         0V         0V
